VERSION 5.7 ;
  NOWIREEXTENSIONATPIN ON ;
  DIVIDERCHAR "/" ;
  BUSBITCHARS "[]" ;
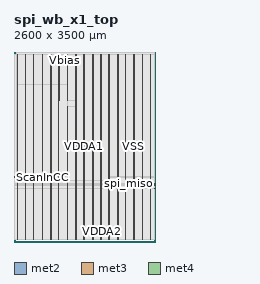
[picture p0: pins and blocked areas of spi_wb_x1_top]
MACRO spi_wb_x1_top
  CLASS BLOCK ;
  FOREIGN spi_wb_x1_top ;
  ORIGIN 0.000 0.000 ;
  SIZE 2600.000 BY 3500.000 ;
  PIN Bias_comp2
    DIRECTION INPUT ;
    USE SIGNAL ;
    ANTENNAGATEAREA 0.860700 ;
    ANTENNADIFFAREA 0.434700 ;
    PORT
      LAYER met2 ;
        RECT 943.550 3496.000 943.830 3500.000 ;
    END
  END Bias_comp2
  PIN Iref
    DIRECTION INPUT ;
    USE SIGNAL ;
    ANTENNAGATEAREA 0.860700 ;
    ANTENNADIFFAREA 0.434700 ;
    PORT
      LAYER met2 ;
        RECT 930.670 3496.000 930.950 3500.000 ;
    END
  END Iref
  PIN ScanInCC
    DIRECTION INPUT ;
    USE SIGNAL ;
    ANTENNAGATEAREA 0.929700 ;
    ANTENNADIFFAREA 0.434700 ;
    PORT
      LAYER met3 ;
        RECT 0.000 1193.440 4.000 1194.040 ;
    END
  END ScanInCC
  PIN ScanInDL
    DIRECTION INPUT ;
    USE SIGNAL ;
    ANTENNAGATEAREA 0.929700 ;
    ANTENNADIFFAREA 0.434700 ;
    PORT
      LAYER met3 ;
        RECT 0.000 1196.840 4.000 1197.440 ;
    END
  END ScanInDL
  PIN ScanInDR
    DIRECTION INPUT ;
    USE SIGNAL ;
    ANTENNAGATEAREA 0.929700 ;
    ANTENNADIFFAREA 0.434700 ;
    PORT
      LAYER met3 ;
        RECT 0.000 1203.640 4.000 1204.240 ;
    END
  END ScanInDR
  PIN ScanOutCC
    DIRECTION OUTPUT ;
    USE SIGNAL ;
    ANTENNADIFFAREA 0.795200 ;
    PORT
      LAYER met3 ;
        RECT 0.000 1207.040 4.000 1207.640 ;
    END
  END ScanOutCC
  PIN TM
    DIRECTION INPUT ;
    USE SIGNAL ;
    ANTENNAGATEAREA 0.929700 ;
    ANTENNADIFFAREA 0.434700 ;
    PORT
      LAYER met3 ;
        RECT 0.000 1200.240 4.000 1200.840 ;
    END
  END TM
  PIN VDDA1
    DIRECTION INOUT ;
    USE POWER ;
    PORT
      LAYER met4 ;
        RECT 683.140 40.560 684.740 3460.080 ;
    END
    PORT
      LAYER met4 ;
        RECT 836.740 2615.525 838.340 3460.080 ;
    END
    PORT
      LAYER met4 ;
        RECT 990.340 2615.525 991.940 3460.080 ;
    END
    PORT
      LAYER met4 ;
        RECT 1143.940 40.560 1145.540 3460.080 ;
    END
    PORT
      LAYER met4 ;
        RECT 1297.540 40.560 1299.140 3460.080 ;
    END
    PORT
      LAYER met4 ;
        RECT 1451.140 40.560 1452.740 3460.080 ;
    END
    PORT
      LAYER met4 ;
        RECT 1604.740 40.560 1606.340 3460.080 ;
    END
    PORT
      LAYER met4 ;
        RECT 1758.340 40.560 1759.940 3460.080 ;
    END
    PORT
      LAYER met4 ;
        RECT 1911.940 40.560 1913.540 3460.080 ;
    END
  END VDDA1
  PIN VDDA2
    DIRECTION INOUT ;
    USE POWER ;
    PORT
      LAYER met4 ;
        RECT 1304.140 40.560 1305.740 3460.080 ;
    END
    PORT
      LAYER met4 ;
        RECT 1457.740 40.560 1459.340 3460.080 ;
    END
    PORT
      LAYER met4 ;
        RECT 1611.340 40.560 1612.940 3460.080 ;
    END
    PORT
      LAYER met4 ;
        RECT 1764.940 40.560 1766.540 3460.080 ;
    END
    PORT
      LAYER met4 ;
        RECT 1918.540 40.560 1920.140 3460.080 ;
    END
  END VDDA2
  PIN VDDC1
    DIRECTION INOUT ;
    USE POWER ;
    PORT
      LAYER met4 ;
        RECT 55.540 40.560 57.140 3460.080 ;
    END
    PORT
      LAYER met4 ;
        RECT 209.140 40.560 210.740 3460.080 ;
    END
    PORT
      LAYER met4 ;
        RECT 362.740 40.560 364.340 3460.080 ;
    END
    PORT
      LAYER met4 ;
        RECT 516.340 40.560 517.940 3460.080 ;
    END
    PORT
      LAYER met4 ;
        RECT 669.940 40.560 671.540 3460.080 ;
    END
    PORT
      LAYER met4 ;
        RECT 823.540 40.560 825.140 3460.080 ;
    END
    PORT
      LAYER met4 ;
        RECT 977.140 40.560 978.740 2502.625 ;
    END
    PORT
      LAYER met4 ;
        RECT 977.140 2615.525 978.740 3460.080 ;
    END
    PORT
      LAYER met4 ;
        RECT 1130.740 40.560 1132.340 3460.080 ;
    END
    PORT
      LAYER met4 ;
        RECT 1284.340 40.560 1285.940 3460.080 ;
    END
    PORT
      LAYER met4 ;
        RECT 1437.940 40.560 1439.540 3460.080 ;
    END
    PORT
      LAYER met4 ;
        RECT 1591.540 40.560 1593.140 3460.080 ;
    END
    PORT
      LAYER met4 ;
        RECT 1745.140 40.560 1746.740 3460.080 ;
    END
    PORT
      LAYER met4 ;
        RECT 1898.740 40.560 1900.340 3460.080 ;
    END
    PORT
      LAYER met4 ;
        RECT 2052.340 40.560 2053.940 3460.080 ;
    END
    PORT
      LAYER met4 ;
        RECT 2205.940 40.560 2207.540 3460.080 ;
    END
    PORT
      LAYER met4 ;
        RECT 2359.540 40.560 2361.140 3460.080 ;
    END
    PORT
      LAYER met4 ;
        RECT 2513.140 40.560 2514.740 3460.080 ;
    END
  END VDDC1
  PIN VDDC2
    DIRECTION INOUT ;
    USE POWER ;
    PORT
      LAYER met4 ;
        RECT 676.540 40.560 678.140 3460.080 ;
    END
    PORT
      LAYER met4 ;
        RECT 830.140 2615.525 831.740 3460.080 ;
    END
    PORT
      LAYER met4 ;
        RECT 983.740 2615.525 985.340 3460.080 ;
    END
    PORT
      LAYER met4 ;
        RECT 1137.340 40.560 1138.940 3460.080 ;
    END
    PORT
      LAYER met4 ;
        RECT 1290.940 40.560 1292.540 3460.080 ;
    END
    PORT
      LAYER met4 ;
        RECT 1444.540 40.560 1446.140 3460.080 ;
    END
    PORT
      LAYER met4 ;
        RECT 1598.140 40.560 1599.740 3460.080 ;
    END
    PORT
      LAYER met4 ;
        RECT 1751.740 40.560 1753.340 3460.080 ;
    END
    PORT
      LAYER met4 ;
        RECT 1905.340 40.560 1906.940 3460.080 ;
    END
  END VDDC2
  PIN VSS
    DIRECTION INOUT ;
    USE GROUND ;
    PORT
      LAYER met4 ;
        RECT 58.840 40.560 60.440 3460.080 ;
    END
    PORT
      LAYER met4 ;
        RECT 212.440 40.560 214.040 3460.080 ;
    END
    PORT
      LAYER met4 ;
        RECT 366.040 40.560 367.640 3460.080 ;
    END
    PORT
      LAYER met4 ;
        RECT 519.640 40.560 521.240 3460.080 ;
    END
    PORT
      LAYER met4 ;
        RECT 673.240 40.560 674.840 3460.080 ;
    END
    PORT
      LAYER met4 ;
        RECT 826.840 40.560 828.440 3460.080 ;
    END
    PORT
      LAYER met4 ;
        RECT 980.440 40.560 982.040 2502.625 ;
    END
    PORT
      LAYER met4 ;
        RECT 980.440 2615.525 982.040 3460.080 ;
    END
    PORT
      LAYER met4 ;
        RECT 1134.040 40.560 1135.640 3460.080 ;
    END
    PORT
      LAYER met4 ;
        RECT 1287.640 40.560 1289.240 3460.080 ;
    END
    PORT
      LAYER met4 ;
        RECT 1441.240 40.560 1442.840 3460.080 ;
    END
    PORT
      LAYER met4 ;
        RECT 1594.840 40.560 1596.440 3460.080 ;
    END
    PORT
      LAYER met4 ;
        RECT 1748.440 40.560 1750.040 3460.080 ;
    END
    PORT
      LAYER met4 ;
        RECT 1902.040 40.560 1903.640 3460.080 ;
    END
    PORT
      LAYER met4 ;
        RECT 2055.640 40.560 2057.240 3460.080 ;
    END
    PORT
      LAYER met4 ;
        RECT 2209.240 40.560 2210.840 3460.080 ;
    END
    PORT
      LAYER met4 ;
        RECT 2362.840 40.560 2364.440 3460.080 ;
    END
    PORT
      LAYER met4 ;
        RECT 2516.440 40.560 2518.040 3460.080 ;
    END
  END VSS
  PIN Vbias
    DIRECTION INPUT ;
    USE SIGNAL ;
    ANTENNAGATEAREA 0.860700 ;
    ANTENNADIFFAREA 0.434700 ;
    PORT
      LAYER met2 ;
        RECT 937.110 3496.000 937.390 3500.000 ;
    END
  END Vbias
  PIN Vcc_read
    DIRECTION INPUT ;
    USE SIGNAL ;
    ANTENNAGATEAREA 1.500000 ;
    ANTENNADIFFAREA 0.434700 ;
    PORT
      LAYER met2 ;
        RECT 1658.390 3496.000 1658.670 3500.000 ;
    END
  END Vcc_read
  PIN Vcc_set
    DIRECTION INPUT ;
    USE SIGNAL ;
    ANTENNAGATEAREA 0.682200 ;
    ANTENNADIFFAREA 0.434700 ;
    PORT
      LAYER met2 ;
        RECT 1661.610 3496.000 1661.890 3500.000 ;
    END
  END Vcc_set
  PIN Vcc_wl_read
    DIRECTION INPUT ;
    USE SIGNAL ;
    ANTENNAGATEAREA 0.682200 ;
    ANTENNADIFFAREA 0.434700 ;
    PORT
      LAYER met2 ;
        RECT 660.190 3496.000 660.470 3500.000 ;
    END
  END Vcc_wl_read
  PIN Vcc_wl_reset
    DIRECTION INPUT ;
    USE SIGNAL ;
    ANTENNAGATEAREA 0.682200 ;
    ANTENNADIFFAREA 0.434700 ;
    PORT
      LAYER met2 ;
        RECT 663.410 3496.000 663.690 3500.000 ;
    END
  END Vcc_wl_reset
  PIN Vcc_wl_set
    DIRECTION INPUT ;
    USE SIGNAL ;
    ANTENNAGATEAREA 0.682200 ;
    ANTENNADIFFAREA 0.434700 ;
    PORT
      LAYER met2 ;
        RECT 666.630 3496.000 666.910 3500.000 ;
    END
  END Vcc_wl_set
  PIN Vcomp
    DIRECTION INPUT ;
    USE SIGNAL ;
    ANTENNAGATEAREA 0.860700 ;
    ANTENNADIFFAREA 0.434700 ;
    PORT
      LAYER met2 ;
        RECT 933.890 3496.000 934.170 3500.000 ;
    END
  END Vcomp
  PIN clk
    DIRECTION INPUT ;
    USE SIGNAL ;
    ANTENNAGATEAREA 1.286700 ;
    ANTENNADIFFAREA 0.434700 ;
    PORT
      LAYER met3 ;
        RECT 0.000 1190.040 4.000 1190.640 ;
    END
  END clk
  PIN dc_bias
    DIRECTION INPUT ;
    USE SIGNAL ;
    ANTENNAGATEAREA 0.860700 ;
    ANTENNADIFFAREA 0.434700 ;
    PORT
      LAYER met2 ;
        RECT 940.330 3496.000 940.610 3500.000 ;
    END
  END dc_bias
  PIN rst
    DIRECTION INPUT ;
    USE SIGNAL ;
    ANTENNAGATEAREA 1.177200 ;
    ANTENNADIFFAREA 0.434700 ;
    PORT
      LAYER met3 ;
        RECT 2596.000 986.040 2600.000 986.640 ;
    END
  END rst
  PIN spi_cs_n
    DIRECTION INPUT ;
    USE SIGNAL ;
    ANTENNAGATEAREA 0.929700 ;
    ANTENNADIFFAREA 0.434700 ;
    PORT
      LAYER met3 ;
        RECT 2596.000 1043.840 2600.000 1044.440 ;
    END
  END spi_cs_n
  PIN spi_miso
    DIRECTION OUTPUT ;
    USE SIGNAL ;
    ANTENNADIFFAREA 0.795200 ;
    PORT
      LAYER met3 ;
        RECT 2596.000 1084.640 2600.000 1085.240 ;
    END
  END spi_miso
  PIN spi_mosi
    DIRECTION INPUT ;
    USE SIGNAL ;
    ANTENNAGATEAREA 1.177200 ;
    ANTENNADIFFAREA 0.434700 ;
    PORT
      LAYER met3 ;
        RECT 2596.000 1064.240 2600.000 1064.840 ;
    END
  END spi_mosi
  PIN spi_sclk
    DIRECTION INPUT ;
    USE SIGNAL ;
    ANTENNAGATEAREA 0.682200 ;
    ANTENNADIFFAREA 0.434700 ;
    PORT
      LAYER met3 ;
        RECT 2596.000 1040.440 2600.000 1041.040 ;
    END
  END spi_sclk
  OBS
      LAYER nwell ;
        RECT 39.830 40.715 2560.090 3460.030 ;
      LAYER li1 ;
        RECT 40.020 40.715 2559.900 3459.925 ;
      LAYER met1 ;
        RECT 40.020 40.560 2587.890 3491.760 ;
      LAYER met2 ;
        RECT 41.490 3495.720 659.910 3496.290 ;
        RECT 660.750 3495.720 663.130 3496.290 ;
        RECT 663.970 3495.720 666.350 3496.290 ;
        RECT 667.190 3495.720 930.390 3496.290 ;
        RECT 931.230 3495.720 933.610 3496.290 ;
        RECT 934.450 3495.720 936.830 3496.290 ;
        RECT 937.670 3495.720 940.050 3496.290 ;
        RECT 940.890 3495.720 943.270 3496.290 ;
        RECT 944.110 3495.720 1658.110 3496.290 ;
        RECT 1658.950 3495.720 1661.330 3496.290 ;
        RECT 1662.170 3495.720 2587.870 3496.290 ;
        RECT 41.490 40.615 2587.870 3495.720 ;
      LAYER met3 ;
        RECT 4.000 1208.040 2596.000 3460.005 ;
        RECT 4.400 1206.640 2596.000 1208.040 ;
        RECT 4.000 1204.640 2596.000 1206.640 ;
        RECT 4.400 1203.240 2596.000 1204.640 ;
        RECT 4.000 1201.240 2596.000 1203.240 ;
        RECT 4.400 1199.840 2596.000 1201.240 ;
        RECT 4.000 1197.840 2596.000 1199.840 ;
        RECT 4.400 1196.440 2596.000 1197.840 ;
        RECT 4.000 1194.440 2596.000 1196.440 ;
        RECT 4.400 1193.040 2596.000 1194.440 ;
        RECT 4.000 1191.040 2596.000 1193.040 ;
        RECT 4.400 1189.640 2596.000 1191.040 ;
        RECT 4.000 1085.640 2596.000 1189.640 ;
        RECT 4.000 1084.240 2595.600 1085.640 ;
        RECT 4.000 1065.240 2596.000 1084.240 ;
        RECT 4.000 1063.840 2595.600 1065.240 ;
        RECT 4.000 1044.840 2596.000 1063.840 ;
        RECT 4.000 1043.440 2595.600 1044.840 ;
        RECT 4.000 1041.440 2596.000 1043.440 ;
        RECT 4.000 1040.040 2595.600 1041.440 ;
        RECT 4.000 987.040 2596.000 1040.040 ;
        RECT 4.000 985.640 2595.600 987.040 ;
        RECT 4.000 40.635 2596.000 985.640 ;
      LAYER met4 ;
        RECT 44.950 1133.055 55.140 3457.625 ;
        RECT 57.540 1133.055 58.440 3457.625 ;
        RECT 60.840 1133.055 208.740 3457.625 ;
        RECT 211.140 1133.055 212.040 3457.625 ;
        RECT 214.440 1133.055 362.340 3457.625 ;
        RECT 364.740 1133.055 365.640 3457.625 ;
        RECT 368.040 1133.055 515.940 3457.625 ;
        RECT 518.340 1133.055 519.240 3457.625 ;
        RECT 521.640 1133.055 669.540 3457.625 ;
        RECT 671.940 1133.055 672.840 3457.625 ;
        RECT 675.240 1133.055 676.140 3457.625 ;
        RECT 678.540 1133.055 682.740 3457.625 ;
        RECT 685.140 1133.055 823.140 3457.625 ;
        RECT 825.540 1133.055 826.440 3457.625 ;
        RECT 828.840 2615.125 829.740 3457.625 ;
        RECT 832.140 2615.125 836.340 3457.625 ;
        RECT 838.740 2615.125 976.740 3457.625 ;
        RECT 979.140 2615.125 980.040 3457.625 ;
        RECT 982.440 2615.125 983.340 3457.625 ;
        RECT 985.740 2615.125 989.940 3457.625 ;
        RECT 992.340 2615.125 1130.340 3457.625 ;
        RECT 828.840 2503.025 1130.340 2615.125 ;
        RECT 828.840 1133.055 976.740 2503.025 ;
        RECT 979.140 1133.055 980.040 2503.025 ;
        RECT 982.440 1133.055 1130.340 2503.025 ;
        RECT 1132.740 1133.055 1133.640 3457.625 ;
        RECT 1136.040 1133.055 1136.940 3457.625 ;
        RECT 1139.340 1133.055 1143.540 3457.625 ;
        RECT 1145.940 1133.055 1283.940 3457.625 ;
        RECT 1286.340 1133.055 1287.240 3457.625 ;
        RECT 1289.640 1133.055 1290.540 3457.625 ;
        RECT 1292.940 1133.055 1297.140 3457.625 ;
        RECT 1299.540 1133.055 1303.740 3457.625 ;
        RECT 1306.140 1133.055 1437.540 3457.625 ;
        RECT 1439.940 1133.055 1440.840 3457.625 ;
        RECT 1443.240 1133.055 1444.140 3457.625 ;
        RECT 1446.540 1133.055 1450.740 3457.625 ;
        RECT 1453.140 1133.055 1457.340 3457.625 ;
        RECT 1459.740 1133.055 1591.140 3457.625 ;
        RECT 1593.540 1133.055 1594.440 3457.625 ;
        RECT 1596.840 1133.055 1597.740 3457.625 ;
        RECT 1600.140 1133.055 1604.340 3457.625 ;
        RECT 1606.740 1133.055 1610.940 3457.625 ;
        RECT 1613.340 1133.055 1736.665 3457.625 ;
      LAYER met5 ;
        RECT 44.740 1207.900 979.220 2895.900 ;
  END
END spi_wb_x1_top
END LIBRARY

